VERSION 5.4 ;
NAMESCASESENSITIVE ON ;
BUSBITCHARS "[]" ;
DIVIDERCHAR "/" ;
UNITS
  DATABASE MICRONS 2000 ;
END UNITS
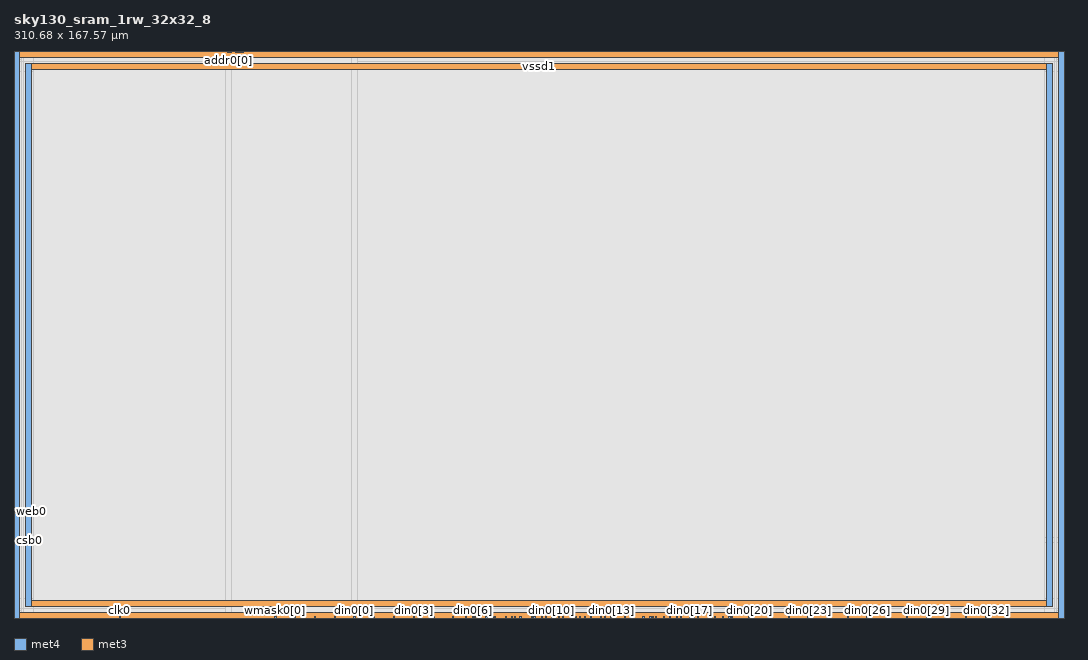
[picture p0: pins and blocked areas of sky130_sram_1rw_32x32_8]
MACRO sky130_sram_1rw_32x32_8
   CLASS BLOCK ;
   SIZE 310.68 BY 167.57 ;
   SYMMETRY X Y R90 ;
   PIN din0[0]
      DIRECTION INPUT ;
      PORT
         LAYER met4 ;
         RECT  100.54 0.0 100.92 0.38 ;
      END
   END din0[0]
   PIN din0[1]
      DIRECTION INPUT ;
      PORT
         LAYER met4 ;
         RECT  106.38 0.0 106.76 0.38 ;
      END
   END din0[1]
   PIN din0[2]
      DIRECTION INPUT ;
      PORT
         LAYER met4 ;
         RECT  112.22 0.0 112.6 0.38 ;
      END
   END din0[2]
   PIN din0[3]
      DIRECTION INPUT ;
      PORT
         LAYER met4 ;
         RECT  118.06 0.0 118.44 0.38 ;
      END
   END din0[3]
   PIN din0[4]
      DIRECTION INPUT ;
      PORT
         LAYER met4 ;
         RECT  123.9 0.0 124.28 0.38 ;
      END
   END din0[4]
   PIN din0[5]
      DIRECTION INPUT ;
      PORT
         LAYER met4 ;
         RECT  129.74 0.0 130.12 0.38 ;
      END
   END din0[5]
   PIN din0[6]
      DIRECTION INPUT ;
      PORT
         LAYER met4 ;
         RECT  135.58 0.0 135.96 0.38 ;
      END
   END din0[6]
   PIN din0[7]
      DIRECTION INPUT ;
      PORT
         LAYER met4 ;
         RECT  141.42 0.0 141.8 0.38 ;
      END
   END din0[7]
   PIN din0[8]
      DIRECTION INPUT ;
      PORT
         LAYER met4 ;
         RECT  147.26 0.0 147.64 0.38 ;
      END
   END din0[8]
   PIN din0[9]
      DIRECTION INPUT ;
      PORT
         LAYER met4 ;
         RECT  153.1 0.0 153.48 0.38 ;
      END
   END din0[9]
   PIN din0[10]
      DIRECTION INPUT ;
      PORT
         LAYER met4 ;
         RECT  158.94 0.0 159.32 0.38 ;
      END
   END din0[10]
   PIN din0[11]
      DIRECTION INPUT ;
      PORT
         LAYER met4 ;
         RECT  164.78 0.0 165.16 0.38 ;
      END
   END din0[11]
   PIN din0[12]
      DIRECTION INPUT ;
      PORT
         LAYER met4 ;
         RECT  170.62 0.0 171.0 0.38 ;
      END
   END din0[12]
   PIN din0[13]
      DIRECTION INPUT ;
      PORT
         LAYER met4 ;
         RECT  176.46 0.0 176.84 0.38 ;
      END
   END din0[13]
   PIN din0[14]
      DIRECTION INPUT ;
      PORT
         LAYER met4 ;
         RECT  182.3 0.0 182.68 0.38 ;
      END
   END din0[14]
   PIN din0[15]
      DIRECTION INPUT ;
      PORT
         LAYER met4 ;
         RECT  188.14 0.0 188.52 0.38 ;
      END
   END din0[15]
   PIN din0[16]
      DIRECTION INPUT ;
      PORT
         LAYER met4 ;
         RECT  193.98 0.0 194.36 0.38 ;
      END
   END din0[16]
   PIN din0[17]
      DIRECTION INPUT ;
      PORT
         LAYER met4 ;
         RECT  199.82 0.0 200.2 0.38 ;
      END
   END din0[17]
   PIN din0[18]
      DIRECTION INPUT ;
      PORT
         LAYER met4 ;
         RECT  205.66 0.0 206.04 0.38 ;
      END
   END din0[18]
   PIN din0[19]
      DIRECTION INPUT ;
      PORT
         LAYER met4 ;
         RECT  211.5 0.0 211.88 0.38 ;
      END
   END din0[19]
   PIN din0[20]
      DIRECTION INPUT ;
      PORT
         LAYER met4 ;
         RECT  217.34 0.0 217.72 0.38 ;
      END
   END din0[20]
   PIN din0[21]
      DIRECTION INPUT ;
      PORT
         LAYER met4 ;
         RECT  223.18 0.0 223.56 0.38 ;
      END
   END din0[21]
   PIN din0[22]
      DIRECTION INPUT ;
      PORT
         LAYER met4 ;
         RECT  229.02 0.0 229.4 0.38 ;
      END
   END din0[22]
   PIN din0[23]
      DIRECTION INPUT ;
      PORT
         LAYER met4 ;
         RECT  234.86 0.0 235.24 0.38 ;
      END
   END din0[23]
   PIN din0[24]
      DIRECTION INPUT ;
      PORT
         LAYER met4 ;
         RECT  240.7 0.0 241.08 0.38 ;
      END
   END din0[24]
   PIN din0[25]
      DIRECTION INPUT ;
      PORT
         LAYER met4 ;
         RECT  246.54 0.0 246.92 0.38 ;
      END
   END din0[25]
   PIN din0[26]
      DIRECTION INPUT ;
      PORT
         LAYER met4 ;
         RECT  252.38 0.0 252.76 0.38 ;
      END
   END din0[26]
   PIN din0[27]
      DIRECTION INPUT ;
      PORT
         LAYER met4 ;
         RECT  258.22 0.0 258.6 0.38 ;
      END
   END din0[27]
   PIN din0[28]
      DIRECTION INPUT ;
      PORT
         LAYER met4 ;
         RECT  264.06 0.0 264.44 0.38 ;
      END
   END din0[28]
   PIN din0[29]
      DIRECTION INPUT ;
      PORT
         LAYER met4 ;
         RECT  269.9 0.0 270.28 0.38 ;
      END
   END din0[29]
   PIN din0[30]
      DIRECTION INPUT ;
      PORT
         LAYER met4 ;
         RECT  275.74 0.0 276.12 0.38 ;
      END
   END din0[30]
   PIN din0[31]
      DIRECTION INPUT ;
      PORT
         LAYER met4 ;
         RECT  281.58 0.0 281.96 0.38 ;
      END
   END din0[31]
   PIN din0[32]
      DIRECTION INPUT ;
      PORT
         LAYER met4 ;
         RECT  287.42 0.0 287.8 0.38 ;
      END
   END din0[32]
   PIN addr0[0]
      DIRECTION INPUT ;
      PORT
         LAYER met4 ;
         RECT  63.27 167.19 63.65 167.57 ;
      END
   END addr0[0]
   PIN addr0[1]
      DIRECTION INPUT ;
      PORT
         LAYER met4 ;
         RECT  67.625 167.19 68.005 167.57 ;
      END
   END addr0[1]
   PIN addr0[2]
      DIRECTION INPUT ;
      PORT
         LAYER met4 ;
         RECT  63.96 167.19 64.34 167.57 ;
      END
   END addr0[2]
   PIN addr0[3]
      DIRECTION INPUT ;
      PORT
         LAYER met4 ;
         RECT  66.935 167.19 67.315 167.57 ;
      END
   END addr0[3]
   PIN addr0[4]
      DIRECTION INPUT ;
      PORT
         LAYER met4 ;
         RECT  66.245 167.19 66.625 167.57 ;
      END
   END addr0[4]
   PIN addr0[5]
      DIRECTION INPUT ;
      PORT
         LAYER met4 ;
         RECT  65.5 167.19 65.88 167.57 ;
      END
   END addr0[5]
   PIN csb0
      DIRECTION INPUT ;
      PORT
         LAYER met3 ;
         RECT  0.0 22.83 0.38 23.21 ;
      END
   END csb0
   PIN web0
      DIRECTION INPUT ;
      PORT
         LAYER met3 ;
         RECT  0.0 31.33 0.38 31.71 ;
      END
   END web0
   PIN clk0
      DIRECTION INPUT ;
      PORT
         LAYER met4 ;
         RECT  31.1 0.0 31.48 0.38 ;
      END
   END clk0
   PIN wmask0[0]
      DIRECTION INPUT ;
      PORT
         LAYER met4 ;
         RECT  77.18 0.0 77.56 0.38 ;
      END
   END wmask0[0]
   PIN wmask0[1]
      DIRECTION INPUT ;
      PORT
         LAYER met4 ;
         RECT  83.02 0.0 83.4 0.38 ;
      END
   END wmask0[1]
   PIN wmask0[2]
      DIRECTION INPUT ;
      PORT
         LAYER met4 ;
         RECT  88.86 0.0 89.24 0.38 ;
      END
   END wmask0[2]
   PIN wmask0[3]
      DIRECTION INPUT ;
      PORT
         LAYER met4 ;
         RECT  94.7 0.0 95.08 0.38 ;
      END
   END wmask0[3]
   PIN spare_wen0
      DIRECTION INPUT ;
      PORT
         LAYER met4 ;
         RECT  293.26 0.0 293.64 0.38 ;
      END
   END spare_wen0
   PIN dout0[0]
      DIRECTION OUTPUT ;
      PORT
         LAYER met4 ;
         RECT  133.6 0.0 133.98 0.38 ;
      END
   END dout0[0]
   PIN dout0[1]
      DIRECTION OUTPUT ;
      PORT
         LAYER met4 ;
         RECT  136.27 0.0 136.65 0.38 ;
      END
   END dout0[1]
   PIN dout0[2]
      DIRECTION OUTPUT ;
      PORT
         LAYER met4 ;
         RECT  137.22 0.0 137.6 0.38 ;
      END
   END dout0[2]
   PIN dout0[3]
      DIRECTION OUTPUT ;
      PORT
         LAYER met4 ;
         RECT  139.615 0.0 139.995 0.38 ;
      END
   END dout0[3]
   PIN dout0[4]
      DIRECTION OUTPUT ;
      PORT
         LAYER met4 ;
         RECT  142.22 0.0 142.6 0.38 ;
      END
   END dout0[4]
   PIN dout0[5]
      DIRECTION OUTPUT ;
      PORT
         LAYER met4 ;
         RECT  145.455 0.0 145.835 0.38 ;
      END
   END dout0[5]
   PIN dout0[6]
      DIRECTION OUTPUT ;
      PORT
         LAYER met4 ;
         RECT  147.95 0.0 148.33 0.38 ;
      END
   END dout0[6]
   PIN dout0[7]
      DIRECTION OUTPUT ;
      PORT
         LAYER met4 ;
         RECT  149.69 0.0 150.07 0.38 ;
      END
   END dout0[7]
   PIN dout0[8]
      DIRECTION OUTPUT ;
      PORT
         LAYER met4 ;
         RECT  153.79 0.0 154.17 0.38 ;
      END
   END dout0[8]
   PIN dout0[9]
      DIRECTION OUTPUT ;
      PORT
         LAYER met4 ;
         RECT  156.07 0.0 156.45 0.38 ;
      END
   END dout0[9]
   PIN dout0[10]
      DIRECTION OUTPUT ;
      PORT
         LAYER met4 ;
         RECT  157.135 0.0 157.515 0.38 ;
      END
   END dout0[10]
   PIN dout0[11]
      DIRECTION OUTPUT ;
      PORT
         LAYER met4 ;
         RECT  161.07 0.0 161.45 0.38 ;
      END
   END dout0[11]
   PIN dout0[12]
      DIRECTION OUTPUT ;
      PORT
         LAYER met4 ;
         RECT  162.22 0.0 162.6 0.38 ;
      END
   END dout0[12]
   PIN dout0[13]
      DIRECTION OUTPUT ;
      PORT
         LAYER met4 ;
         RECT  166.07 0.0 166.45 0.38 ;
      END
   END dout0[13]
   PIN dout0[14]
      DIRECTION OUTPUT ;
      PORT
         LAYER met4 ;
         RECT  167.22 0.0 167.6 0.38 ;
      END
   END dout0[14]
   PIN dout0[15]
      DIRECTION OUTPUT ;
      PORT
         LAYER met4 ;
         RECT  168.815 0.0 169.195 0.38 ;
      END
   END dout0[15]
   PIN dout0[16]
      DIRECTION OUTPUT ;
      PORT
         LAYER met4 ;
         RECT  173.6 0.0 173.98 0.38 ;
      END
   END dout0[16]
   PIN dout0[17]
      DIRECTION OUTPUT ;
      PORT
         LAYER met4 ;
         RECT  174.655 0.0 175.035 0.38 ;
      END
   END dout0[17]
   PIN dout0[18]
      DIRECTION OUTPUT ;
      PORT
         LAYER met4 ;
         RECT  177.22 0.0 177.6 0.38 ;
      END
   END dout0[18]
   PIN dout0[19]
      DIRECTION OUTPUT ;
      PORT
         LAYER met4 ;
         RECT  180.495 0.0 180.875 0.38 ;
      END
   END dout0[19]
   PIN dout0[20]
      DIRECTION OUTPUT ;
      PORT
         LAYER met4 ;
         RECT  182.99 0.0 183.37 0.38 ;
      END
   END dout0[20]
   PIN dout0[21]
      DIRECTION OUTPUT ;
      PORT
         LAYER met4 ;
         RECT  186.07 0.0 186.45 0.38 ;
      END
   END dout0[21]
   PIN dout0[22]
      DIRECTION OUTPUT ;
      PORT
         LAYER met4 ;
         RECT  188.83 0.0 189.21 0.38 ;
      END
   END dout0[22]
   PIN dout0[23]
      DIRECTION OUTPUT ;
      PORT
         LAYER met4 ;
         RECT  189.69 0.0 190.07 0.38 ;
      END
   END dout0[23]
   PIN dout0[24]
      DIRECTION OUTPUT ;
      PORT
         LAYER met4 ;
         RECT  192.175 0.0 192.555 0.38 ;
      END
   END dout0[24]
   PIN dout0[25]
      DIRECTION OUTPUT ;
      PORT
         LAYER met4 ;
         RECT  196.07 0.0 196.45 0.38 ;
      END
   END dout0[25]
   PIN dout0[26]
      DIRECTION OUTPUT ;
      PORT
         LAYER met4 ;
         RECT  197.22 0.0 197.6 0.38 ;
      END
   END dout0[26]
   PIN dout0[27]
      DIRECTION OUTPUT ;
      PORT
         LAYER met4 ;
         RECT  201.07 0.0 201.45 0.38 ;
      END
   END dout0[27]
   PIN dout0[28]
      DIRECTION OUTPUT ;
      PORT
         LAYER met4 ;
         RECT  202.22 0.0 202.6 0.38 ;
      END
   END dout0[28]
   PIN dout0[29]
      DIRECTION OUTPUT ;
      PORT
         LAYER met4 ;
         RECT  206.35 0.0 206.73 0.38 ;
      END
   END dout0[29]
   PIN dout0[30]
      DIRECTION OUTPUT ;
      PORT
         LAYER met4 ;
         RECT  207.22 0.0 207.6 0.38 ;
      END
   END dout0[30]
   PIN dout0[31]
      DIRECTION OUTPUT ;
      PORT
         LAYER met4 ;
         RECT  209.69 0.0 210.07 0.38 ;
      END
   END dout0[31]
   PIN dout0[32]
      DIRECTION OUTPUT ;
      PORT
         LAYER met4 ;
         RECT  212.22 0.0 212.6 0.38 ;
      END
   END dout0[32]
   PIN vccd1
      DIRECTION INOUT ;
      USE POWER ; 
      SHAPE ABUTMENT ; 
      PORT
         LAYER met4 ;
         RECT  0.0 0.0 1.74 167.57 ;
         LAYER met4 ;
         RECT  308.94 0.0 310.68 167.57 ;
         LAYER met3 ;
         RECT  0.0 0.0 310.68 1.74 ;
         LAYER met3 ;
         RECT  0.0 165.83 310.68 167.57 ;
      END
   END vccd1
   PIN vssd1
      DIRECTION INOUT ;
      USE GROUND ; 
      SHAPE ABUTMENT ; 
      PORT
         LAYER met4 ;
         RECT  305.46 3.48 307.2 164.09 ;
         LAYER met3 ;
         RECT  3.48 162.35 307.2 164.09 ;
         LAYER met3 ;
         RECT  3.48 3.48 307.2 5.22 ;
         LAYER met4 ;
         RECT  3.48 3.48 5.22 164.09 ;
      END
   END vssd1
   OBS
   LAYER  met1 ;
      RECT  0.62 0.62 310.06 166.95 ;
   LAYER  met2 ;
      RECT  0.62 0.62 310.06 166.95 ;
   LAYER  met3 ;
      RECT  0.98 22.23 310.06 23.81 ;
      RECT  0.62 23.81 0.98 30.73 ;
      RECT  0.62 2.34 0.98 22.23 ;
      RECT  0.62 32.31 0.98 165.23 ;
      RECT  0.98 23.81 2.88 161.75 ;
      RECT  0.98 161.75 2.88 164.69 ;
      RECT  0.98 164.69 2.88 165.23 ;
      RECT  2.88 23.81 307.8 161.75 ;
      RECT  2.88 164.69 307.8 165.23 ;
      RECT  307.8 23.81 310.06 161.75 ;
      RECT  307.8 161.75 310.06 164.69 ;
      RECT  307.8 164.69 310.06 165.23 ;
      RECT  0.98 2.34 2.88 2.88 ;
      RECT  0.98 2.88 2.88 5.82 ;
      RECT  0.98 5.82 2.88 22.23 ;
      RECT  2.88 2.34 307.8 2.88 ;
      RECT  2.88 5.82 307.8 22.23 ;
      RECT  307.8 2.34 310.06 2.88 ;
      RECT  307.8 2.88 310.06 5.82 ;
      RECT  307.8 5.82 310.06 22.23 ;
   LAYER  met4 ;
      RECT  99.94 0.98 101.52 166.95 ;
      RECT  101.52 0.62 105.78 0.98 ;
      RECT  107.36 0.62 111.62 0.98 ;
      RECT  113.2 0.62 117.46 0.98 ;
      RECT  119.04 0.62 123.3 0.98 ;
      RECT  124.88 0.62 129.14 0.98 ;
      RECT  218.32 0.62 222.58 0.98 ;
      RECT  224.16 0.62 228.42 0.98 ;
      RECT  230.0 0.62 234.26 0.98 ;
      RECT  235.84 0.62 240.1 0.98 ;
      RECT  241.68 0.62 245.94 0.98 ;
      RECT  247.52 0.62 251.78 0.98 ;
      RECT  253.36 0.62 257.62 0.98 ;
      RECT  259.2 0.62 263.46 0.98 ;
      RECT  265.04 0.62 269.3 0.98 ;
      RECT  270.88 0.62 275.14 0.98 ;
      RECT  276.72 0.62 280.98 0.98 ;
      RECT  282.56 0.62 286.82 0.98 ;
      RECT  62.67 0.98 64.25 166.59 ;
      RECT  64.25 0.98 99.94 166.59 ;
      RECT  68.605 166.59 99.94 166.95 ;
      RECT  32.08 0.62 76.58 0.98 ;
      RECT  78.16 0.62 82.42 0.98 ;
      RECT  84.0 0.62 88.26 0.98 ;
      RECT  89.84 0.62 94.1 0.98 ;
      RECT  95.68 0.62 99.94 0.98 ;
      RECT  288.4 0.62 292.66 0.98 ;
      RECT  130.72 0.62 133.0 0.98 ;
      RECT  134.58 0.62 134.98 0.98 ;
      RECT  138.2 0.62 139.015 0.98 ;
      RECT  140.595 0.62 140.82 0.98 ;
      RECT  143.2 0.62 144.855 0.98 ;
      RECT  146.435 0.62 146.66 0.98 ;
      RECT  148.93 0.62 149.09 0.98 ;
      RECT  150.67 0.62 152.5 0.98 ;
      RECT  154.77 0.62 155.47 0.98 ;
      RECT  158.115 0.62 158.34 0.98 ;
      RECT  159.92 0.62 160.47 0.98 ;
      RECT  163.2 0.62 164.18 0.98 ;
      RECT  168.2 0.62 168.215 0.98 ;
      RECT  169.795 0.62 170.02 0.98 ;
      RECT  171.6 0.62 173.0 0.98 ;
      RECT  175.635 0.62 175.86 0.98 ;
      RECT  178.2 0.62 179.895 0.98 ;
      RECT  181.475 0.62 181.7 0.98 ;
      RECT  183.97 0.62 185.47 0.98 ;
      RECT  187.05 0.62 187.54 0.98 ;
      RECT  190.67 0.62 191.575 0.98 ;
      RECT  193.155 0.62 193.38 0.98 ;
      RECT  194.96 0.62 195.47 0.98 ;
      RECT  198.2 0.62 199.22 0.98 ;
      RECT  203.2 0.62 205.06 0.98 ;
      RECT  208.2 0.62 209.09 0.98 ;
      RECT  210.67 0.62 210.9 0.98 ;
      RECT  213.2 0.62 216.74 0.98 ;
      RECT  2.34 166.59 62.67 166.95 ;
      RECT  2.34 0.62 30.5 0.98 ;
      RECT  294.24 0.62 308.34 0.98 ;
      RECT  101.52 0.98 304.86 2.88 ;
      RECT  101.52 2.88 304.86 164.69 ;
      RECT  101.52 164.69 304.86 166.95 ;
      RECT  304.86 0.98 307.8 2.88 ;
      RECT  304.86 164.69 307.8 166.95 ;
      RECT  307.8 0.98 308.34 2.88 ;
      RECT  307.8 2.88 308.34 164.69 ;
      RECT  307.8 164.69 308.34 166.95 ;
      RECT  2.34 0.98 2.88 2.88 ;
      RECT  2.34 2.88 2.88 164.69 ;
      RECT  2.34 164.69 2.88 166.59 ;
      RECT  2.88 0.98 5.82 2.88 ;
      RECT  2.88 164.69 5.82 166.59 ;
      RECT  5.82 0.98 62.67 2.88 ;
      RECT  5.82 2.88 62.67 164.69 ;
      RECT  5.82 164.69 62.67 166.59 ;
   END
END    sky130_sram_1rw_32x32_8
END    LIBRARY
